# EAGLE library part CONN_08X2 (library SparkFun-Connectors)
Multi connection point. Often used as Generic Header-pin footprint for 0.1 inch spaced/style header connections You can populate with any combo of single row headers, but if you'd like an exact match, check this: Header - 2x8 (Male, 0.1") (PRT-13156) On any of the 0.1 inch spaced packages, you can populate with these: Break Away Headers - Straight (PRT-00116) Break Away Male Headers - Right Angle (PRT-00553) Female Headers (PRT-00115) Break Away Headers - Machine Pin (PRT-00117) Break Away Female Headers - Swiss Machine Pin (PRT-00743)

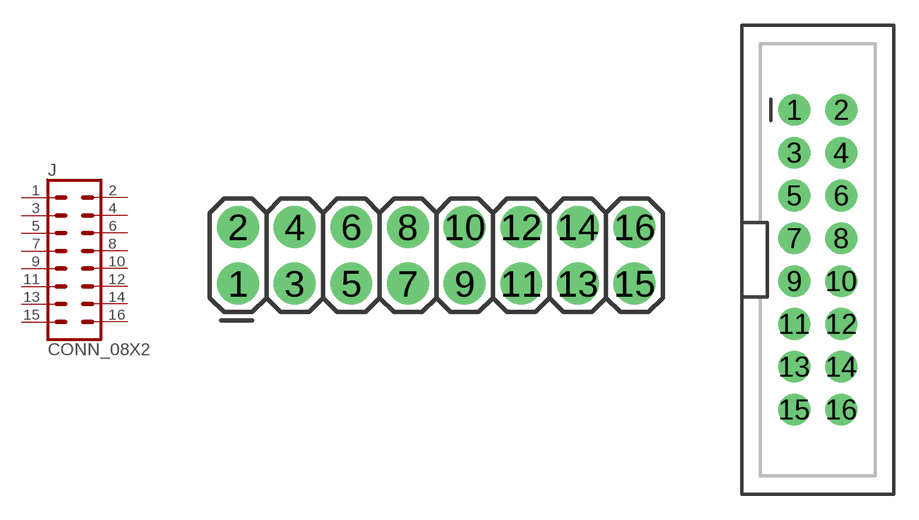
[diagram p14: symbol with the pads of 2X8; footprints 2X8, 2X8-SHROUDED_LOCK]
Designator prefix J

## CONN_08X2_HEADER  [2X8]
1  1  pas
2  2  pas
3  3  pas
4  4  pas
5  5  pas
6  6  pas
7  7  pas
8  8  pas
9  9  pas
10  10  pas
11  11  pas
12  12  pas
13  13  pas
14  14  pas
15  15  pas
16  16  pas

## CONN_08X2_SHROUD  [2X8-SHROUDED_LOCK]
Pads as for 2X8

## CONN_08X2_NOSILK  [2X8_NOSILK]
Pads as for 2X8

## Footprint 2X8 (pad centres in mm)
Plated Through Hole - 2x8 Specifications: Pin count:16 Pin pitch:0.1" Example device(s): CONN_08x2
drill 1.016 pad 1.88: 1 0,0; 2 0,2.54; 3 2.54,0; 4 2.54,2.54; 5 5.08,0; 6 5.08,2.54; 7 7.62,0; 8 7.62,2.54; 9 10.16,0; 10 10.16,2.54; 11 12.7,0; 12 12.7,2.54; 13 15.24,0; 14 15.24,2.54; 15 17.78,0; 16 17.78,2.54

## Footprint 2X8-SHROUDED_LOCK (pad centres in mm)
drill 1.016 pad 1.88: 1 -1.397,8.89; 2 1.397,8.89; 3 -1.397,6.35; 4 1.397,6.35; 5 -1.397,3.81; 6 1.397,3.81; 7 -1.397,1.27; 8 1.397,1.27; 9 -1.397,-1.27; 10 1.397,-1.27; 11 -1.397,-3.81; 12 1.397,-3.81; 13 -1.397,-6.35; 14 1.397,-6.35; 15 -1.397,-8.89; 16 1.397,-8.89

## Footprint 2X8_NOSILK (pad centres in mm)
Plated Through Hole - 2x8 Specifications: Pin count:16 Pin pitch:0.1" Example device(s): CONN_08x2
drill 1.016 pad 1.88: 1 0,0; 2 0,2.54; 3 2.54,0; 4 2.54,2.54; 5 5.08,0; 6 5.08,2.54; 7 7.62,0; 8 7.62,2.54; 9 10.16,0; 10 10.16,2.54; 11 12.7,0; 12 12.7,2.54; 13 15.24,0; 14 15.24,2.54; 15 17.78,0; 16 17.78,2.54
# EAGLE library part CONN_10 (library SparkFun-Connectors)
Multi connection point. Often used as Generic Header-pin footprint for 0.1 inch spaced/style header connections On any of the 0.1 inch spaced packages, you can populate with these: Break Away Headers - Straight (PRT-00116) Break Away Male Headers - Right Angle (PRT-00553) Female Headers (PRT-00115) Break Away Headers - Machine Pin (PRT-00117) Break Away Female Headers - Swiss Machine Pin (PRT-00743) Arduino Stackable Header - 10 Pin (PRT-11376) For SCREWTERMINALS and SPRING TERMINALS visit here: Screw Terimnals on SparkFun.com (5mm/3.5mm/2.54mm spacing) This device is also useful as a general connection point to wire up your design to another part of your project. Our various solder wires solder well into these plated through hole pads. Hook-Up Wire - Assortment (Stranded, 22 AWG) (PRT-11375) Hook-Up Wire - Assortment (Solid Core, 22 AWG) (PRT-11367) View the entire wire category on our website here Special notes: Molex polarized connector foot print use with SKU : PRT-08231 with associated crimp pins and housings. 1MM SMD Version SKU: PRT-10208 NOTES ON THE VARIANTS LOCK and LOCK_LONGPADS... This footprint was designed to help hold the alignment of a through-hole component (i.e. 6-pin header) while soldering it into place. You may notice that each hole has been shifted either up or down by 0.005 of an inch from it's more standard position (which is a perfectly straight line). This slight alteration caused the pins (the squares in the middle) to touch the edges of the holes.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

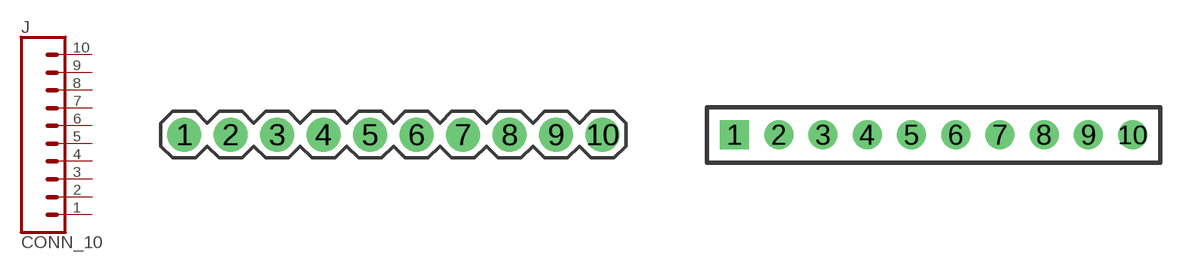
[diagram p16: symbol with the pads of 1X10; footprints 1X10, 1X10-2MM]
Designator prefix J

## CONN_10" (PROD_ID: CONN-11563)  [1X10]
1  1  pas
2  2  pas
3  3  pas
4  4  pas
5  5  pas
6  6  pas
7  7  pas
8  8  pas
9  9  pas
10  10  pas

## CONN_102MM (PROD_ID: CONN-08875; SF_ID: PRT-08272)  [1X10-2MM]
Pads as for 1X10

## CONN_102MMSMD (PROD_ID: CONN-09042; SF_ID: PRT-10030)  [1X10-2MM-SMD]
Pads as for 1X10

## CONN_10LOCK  [1X10_LOCK]
Pads as for 1X10

## CONN_10LOCK_LONGPADS  [1X10_LOCK_LONGPADS]
Pads as for 1X10

## CONN_10SMD_COMBO-FEMALE (PROD_ID: CONN-11219)  [1X10_SMD_COMBINED]
1A  1  pas
1B  1  pas
2A  2  pas
2B  2  pas
3A  3  pas
3B  3  pas
4A  4  pas
4B  4  pas
5A  5  pas
5B  5  pas
6A  6  pas
6B  6  pas
7A  7  pas
7B  7  pas
8A  8  pas
8B  8  pas
9A  9  pas
9B  9  pas
10A  10  pas
10B  10  pas

## CONN_10SMD_MALE (PROD_ID: CONN-11291)  [1X10_SMD_MALE]
Pads as for 1X10

## CONN_10NO_SILK_PTH_FEMALE  [1X10_NO_SILK]
Pads as for 1X10

## CONN_10LOCK_NS  [1X10_LOCK_NS]
Pads as for 1X10

## CONN_101.25MM_SMD  [1X10-1.25MM-SMD]
Pads as for 1X10

## CONN_103.5MM-10 (PROD_ID: CONN-13177)  [SCREWTERMINAL-3.5MM-10]
Pads as for 1X10

## CONN_10FPC_10_0.5MM  [FPC_10_0.5MM]
Pads as for 1X10

## CONN_10_3.5MM_RA_HEADER (PROD_ID: CONN-17279; STOREFRONT: PRT-21328)  [1X10_SCREW_TERMINAL_3.5MM]
Pads as for 1X10

## Footprint 1X10 (pad centres in mm)
Plated Through Hole -10 Pin Specifications: Pin count:10 Pin pitch:0.1" Example device(s): CONN_10
drill 1.016 pad 1.88: 1 0,0; 2 2.54,0; 3 5.08,0; 4 7.62,0; 5 10.16,0; 6 12.7,0; 7 15.24,0; 8 17.78,0; 9 20.32,0; 10 22.86,0

## Footprint 1X10-2MM (pad centres in mm)
Plated Through Hole -10 Pin 2mm Specifications: Pin count:10 Pin pitch:2mm Datasheet referenced for footprint Example device(s): CONN_10
drill 0.8 square: 1 0,0
drill 0.8: 2 2,0; 3 4,0; 4 6,0; 5 8,0; 6 10,0; 7 12,0; 8 14,0; 9 16,0; 10 18,0

## Footprint 1X10-2MM-SMD (pad centres in mm)
Plated Through Hole -10 Pin 2mm SMD Specifications: Pin count:10 Pin pitch:2mm Datasheet referenced for footprint Example device(s): CONN_10
smd 0.85 x 2.1: 1 0,-1.5; 2 2,1.5; 3 4,-1.5; 4 6,1.5; 5 8,-1.5; 6 10,1.5; 7 12,-1.5; 8 14,1.5; 9 16,-1.5; 10 18,1.5

## Footprint 1X10_LOCK (pad centres in mm)
Plated Through Hole -10 Pin Locking Footprint Holes are offset 0.005" to hold pins in place while soldering. Specifications: Pin count:10 Pin pitch:0.1" Example device(s): CONN_10
drill 1.016 pad 1.88: 1 0,0.127; 2 2.54,-0.127; 3 5.08,0.127; 4 7.62,-0.127; 5 10.16,0.127; 6 12.7,-0.127; 7 15.24,0.127; 8 17.78,-0.127; 9 20.32,0.127; 10 22.86,-0.127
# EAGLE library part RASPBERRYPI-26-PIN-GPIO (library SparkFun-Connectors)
RASPBERRY PI I/O HEADER As defined for the Revistion 2 Pi. The 40 pin header is backwards compatible with this smaller more compact footprint.

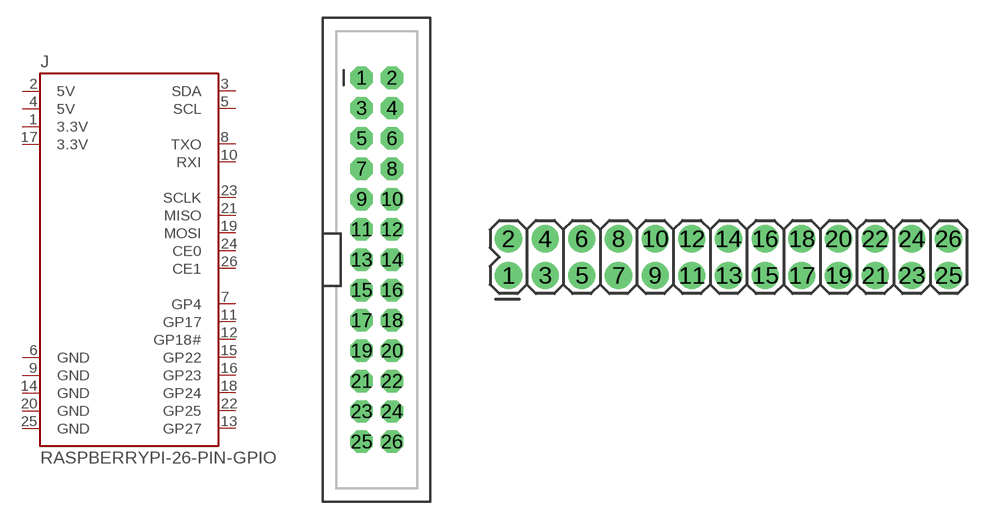
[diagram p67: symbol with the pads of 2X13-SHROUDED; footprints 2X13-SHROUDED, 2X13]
Designator prefix J

## RASPBERRYPI-26-PIN-GPIOPTH (DIST: sparkfun; DIST_ID: PRT-11490)  [2X13-SHROUDED]
1  3.3V  pwr
2  5V  pwr
3  SDA
4  5V  pwr
5  SCL
6  GND  pwr
7  GP4
8  TXO  out
9  GND  pwr
10  RXI  in
11  GP17
12  GP18#
13  GP27
14  GND  pwr
15  GP22
16  GP23
17  3.3V  pwr
18  GP24
19  MOSI  out
20  GND  pwr
21  MISO  in
22  GP25
23  SCLK  out
24  CE0  out
25  GND  pwr
26  CE1  out

## RASPBERRYPI-26-PIN-GPIO  [2X13]
Pads as for 2X13-SHROUDED

## Footprint 2X13-SHROUDED (pad centres in mm)
drill 1.016 pad 1.88 octagon: 1 -1.27,15.24; 2 1.27,15.24; 3 -1.27,12.7; 4 1.27,12.7; 5 -1.27,10.16; 6 1.27,10.16; 7 -1.27,7.62; 8 1.27,7.62; 9 -1.27,5.08; 10 1.27,5.08; 11 -1.27,2.54; 12 1.27,2.54; 13 -1.27,0; 14 1.27,0; 15 -1.27,-2.54; 16 1.27,-2.54; 17 -1.27,-5.08; 18 1.27,-5.08; 19 -1.27,-7.62; 20 1.27,-7.62; 21 -1.27,-10.16; 22 1.27,-10.16; 23 -1.27,-12.7; 24 1.27,-12.7; 25 -1.27,-15.24; 26 1.27,-15.24

## Footprint 2X13 (pad centres in mm)
drill 1.016 pad 1.88: 1 0,0; 2 0,2.54; 3 2.54,0; 4 2.54,2.54; 5 5.08,0; 6 5.08,2.54; 7 7.62,0; 8 7.62,2.54; 9 10.16,0; 10 10.16,2.54; 11 12.7,0; 12 12.7,2.54; 13 15.24,0; 14 15.24,2.54; 15 17.78,0; 16 17.78,2.54; 17 20.32,0; 18 20.32,2.54; 19 22.86,0; 20 22.86,2.54; 21 25.4,0; 22 25.4,2.54; 23 27.94,0; 24 27.94,2.54; 25 30.48,0; 26 30.48,2.54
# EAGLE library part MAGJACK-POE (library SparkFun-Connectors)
MAGJACK: RJ-45 with POE and LEDs This is a single port, RJ45 ethernet jacks with built in transformer (magnetics), PoE rectifier diodes, status LEDs, and shielding.

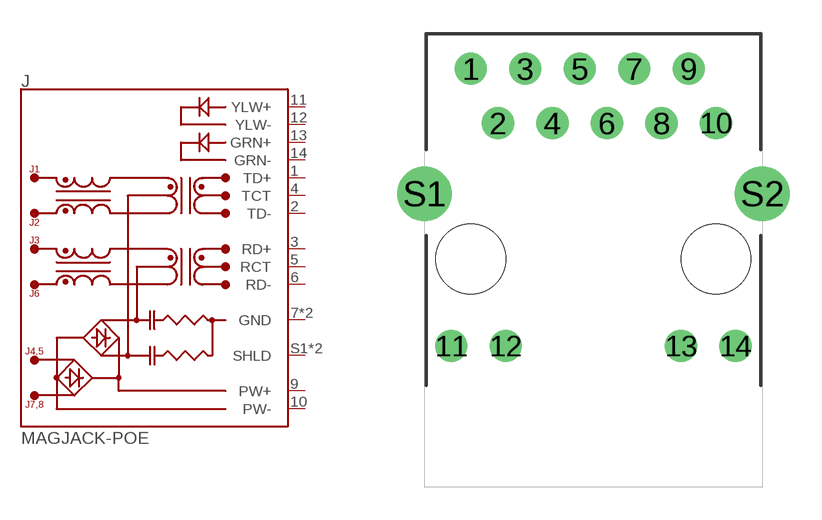
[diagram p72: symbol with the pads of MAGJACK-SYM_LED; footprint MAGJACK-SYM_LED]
Designator prefix J

## MAGJACK-POE (PROD_ID: CONN-16253)  [MAGJACK-SYM_LED]
1  TD+
2  TD-
3  RD+
4  TCT
5  RCT
6  RD-
7  GND
8  GND
9  PW+
10  PW-
11  YLW+
12  YLW-
13  GRN+
14  GRN-
S1  SHLD
S2  SHLD

## Footprint MAGJACK-SYM_LED (pad centres in mm)
LPJ0284GDNL, HR861153C
drill 0.9 pad 1.5: 1 -5.715,8.89; 2 -4.445,6.35; 3 -3.175,8.89; 4 -1.905,6.35; 5 -0.635,8.89; 6 0.635,6.35; 7 1.905,8.89; 8 3.175,6.35; 9 4.445,8.89; 10 5.715,6.35; 11 -6.63,-4.06; 12 -4.09,-4.06; 13 4.09,-4.06; 14 6.63,-4.06
drill 1.7 pad 2.4: S1 -7.875,3.05; S2 7.875,3.05
hole 3.25 at -5.715,0
hole 3.25 at 5.715,0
